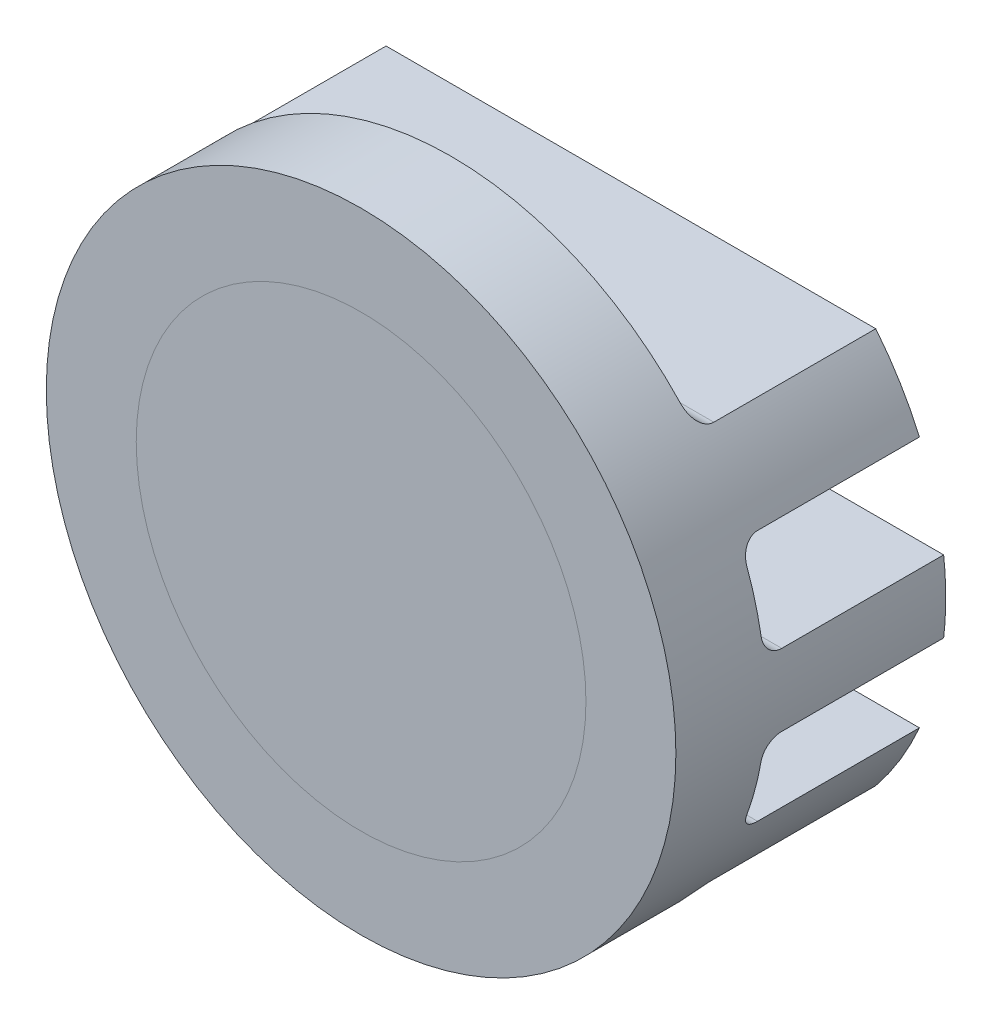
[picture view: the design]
ISO-10303-21;
HEADER;
FILE_DESCRIPTION(('STEP AP214'),'2;1');
FILE_NAME('part.step','',(''),(''),'','','');
FILE_SCHEMA(('AUTOMOTIVE_DESIGN { 1 0 10303 214 1 1 1 1 }'));
ENDSEC;
DATA;
#1=APPLICATION_CONTEXT('core data for automotive mechanical design processes');
#2=APPLICATION_PROTOCOL_DEFINITION('international standard','automotive_design',2000,#1);
#3=PRODUCT_CONTEXT('',#1,'mechanical');
#4=PRODUCT('Part','Part','',(#3));
#5=PRODUCT_RELATED_PRODUCT_CATEGORY('part','',(#4));
#6=PRODUCT_DEFINITION_FORMATION('','',#4);
#7=PRODUCT_DEFINITION_CONTEXT('part definition',#1,'design');
#8=PRODUCT_DEFINITION('design','',#6,#7);
#9=PRODUCT_DEFINITION_SHAPE('','',#8);
#10=(LENGTH_UNIT() NAMED_UNIT(*) SI_UNIT(.MILLI.,.METRE.));
#11=(NAMED_UNIT(*) PLANE_ANGLE_UNIT() SI_UNIT($,.RADIAN.));
#12=(NAMED_UNIT(*) SI_UNIT($,.STERADIAN.) SOLID_ANGLE_UNIT());
#13=UNCERTAINTY_MEASURE_WITH_UNIT(LENGTH_MEASURE(1.E-05),#10,'distance_accuracy_value','');
#14=(GEOMETRIC_REPRESENTATION_CONTEXT(3) GLOBAL_UNCERTAINTY_ASSIGNED_CONTEXT((#13)) GLOBAL_UNIT_ASSIGNED_CONTEXT((#10,
#11,#12)) REPRESENTATION_CONTEXT('',''));
#15=CARTESIAN_POINT('',(0.,0.,0.));
#16=DIRECTION('',(0.,0.,1.));
#17=DIRECTION('',(1.,0.,0.));
#18=AXIS2_PLACEMENT_3D('',#15,#16,#17);
#19=CARTESIAN_POINT('',(43.,4.,-20.));
#20=DIRECTION('',(0.,0.,1.));
#21=DIRECTION('',(1.,0.,0.));
#22=AXIS2_PLACEMENT_3D('',#19,#20,#21);
#23=PLANE('',#22);
#24=DIRECTION('',(-1.,0.,0.));
#25=VECTOR('',#24,1.);
#26=CARTESIAN_POINT('',(43.,0.,-20.));
#27=LINE('',#26,#25);
#28=CARTESIAN_POINT('',(0.,0.,-20.));
#29=VERTEX_POINT('',#28);
#30=CARTESIAN_POINT('',(-35.,0.,-20.));
#31=VERTEX_POINT('',#30);
#32=EDGE_CURVE('E12',#29,#31,#27,.T.);
#33=ORIENTED_EDGE('',*,*,#32,.F.);
#34=DIRECTION('',(0.,-1.,0.));
#35=VECTOR('',#34,1.);
#36=CARTESIAN_POINT('',(0.,4.,-20.));
#37=LINE('',#36,#35);
#38=CARTESIAN_POINT('',(0.,-4.,-20.));
#39=VERTEX_POINT('',#38);
#40=EDGE_CURVE('E357',#29,#39,#37,.T.);
#41=ORIENTED_EDGE('',*,*,#40,.T.);
#42=DIRECTION('',(-1.,0.,0.));
#43=VECTOR('',#42,1.);
#44=CARTESIAN_POINT('',(43.,-4.,-20.));
#45=LINE('',#44,#43);
#46=CARTESIAN_POINT('',(-34.7706773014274,-4.,-20.));
#47=VERTEX_POINT('',#46);
#48=EDGE_CURVE('E234',#39,#47,#45,.T.);
#49=ORIENTED_EDGE('',*,*,#48,.T.);
#50=CARTESIAN_POINT('',(0.,0.,-20.));
#51=DIRECTION('',(0.,0.,1.));
#52=DIRECTION('',(1.,0.,0.));
#53=AXIS2_PLACEMENT_3D('',#50,#51,#52);
#54=CIRCLE('',#53,35.);
#55=EDGE_CURVE('E189',#31,#47,#54,.T.);
#56=ORIENTED_EDGE('',*,*,#55,.F.);
#57=EDGE_LOOP('',(#33,#41,#49,#56));
#58=FACE_BOUND('',#57,.T.);
#59=ADVANCED_FACE('F39',(#58),#23,.F.);
#60=DIRECTION('',(-1.,0.,0.));
#61=VECTOR('',#60,1.);
#62=CARTESIAN_POINT('',(43.,0.,-20.));
#63=LINE('',#62,#61);
#64=CARTESIAN_POINT('',(35.,0.,-20.));
#65=VERTEX_POINT('',#64);
#66=EDGE_CURVE('E44',#65,#29,#63,.T.);
#67=ORIENTED_EDGE('',*,*,#66,.F.);
#68=CARTESIAN_POINT('',(34.7706773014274,-4.,-20.));
#69=VERTEX_POINT('',#68);
#70=EDGE_CURVE('E185',#69,#65,#54,.T.);
#71=ORIENTED_EDGE('',*,*,#70,.F.);
#72=EDGE_CURVE('E198',#69,#39,#45,.T.);
#73=ORIENTED_EDGE('',*,*,#72,.T.);
#74=ORIENTED_EDGE('',*,*,#40,.F.);
#75=EDGE_LOOP('',(#67,#71,#73,#74));
#76=FACE_BOUND('',#75,.T.);
#77=ADVANCED_FACE('F351',(#76),#23,.F.);
#78=CARTESIAN_POINT('',(34.7706773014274,4.,-20.));
#79=VERTEX_POINT('',#78);
#80=EDGE_CURVE('E181',#65,#79,#54,.T.);
#81=ORIENTED_EDGE('',*,*,#80,.F.);
#82=ORIENTED_EDGE('',*,*,#66,.T.);
#83=CARTESIAN_POINT('',(0.,4.,-20.));
#84=VERTEX_POINT('',#83);
#85=EDGE_CURVE('E193',#84,#29,#37,.T.);
#86=ORIENTED_EDGE('',*,*,#85,.F.);
#87=DIRECTION('',(1.,0.,0.));
#88=VECTOR('',#87,1.);
#89=CARTESIAN_POINT('',(43.,4.,-20.));
#90=LINE('',#89,#88);
#91=EDGE_CURVE('E191',#84,#79,#90,.T.);
#92=ORIENTED_EDGE('',*,*,#91,.T.);
#93=EDGE_LOOP('',(#81,#82,#86,#92));
#94=FACE_BOUND('',#93,.T.);
#95=ADVANCED_FACE('F192',(#94),#23,.F.);
#96=CARTESIAN_POINT('',(0.,0.,10.));
#97=DIRECTION('',(0.,0.,1.));
#98=DIRECTION('',(1.,0.,0.));
#99=AXIS2_PLACEMENT_3D('',#96,#97,#98);
#100=PLANE('',#99);
#101=CARTESIAN_POINT('',(0.,0.,10.));
#102=DIRECTION('',(0.,0.,1.));
#103=DIRECTION('',(1.,0.,0.));
#104=AXIS2_PLACEMENT_3D('',#101,#102,#103);
#105=CIRCLE('',#104,35.);
#106=CARTESIAN_POINT('',(35.,0.,10.));
#107=VERTEX_POINT('',#106);
#108=EDGE_CURVE('E243',#107,#107,#105,.T.);
#109=ORIENTED_EDGE('',*,*,#108,.T.);
#110=EDGE_LOOP('',(#109));
#111=FACE_BOUND('',#110,.T.);
#112=CARTESIAN_POINT('',(0.,0.,10.));
#113=DIRECTION('',(0.,0.,1.));
#114=DIRECTION('',(1.,0.,0.));
#115=AXIS2_PLACEMENT_3D('',#112,#113,#114);
#116=CIRCLE('',#115,25.);
#117=CARTESIAN_POINT('',(25.,0.,10.));
#118=VERTEX_POINT('',#117);
#119=EDGE_CURVE('E363',#118,#118,#116,.F.);
#120=ORIENTED_EDGE('',*,*,#119,.T.);
#121=EDGE_LOOP('',(#120));
#122=FACE_BOUND('',#121,.T.);
#123=ADVANCED_FACE('F334',(#111,#122),#100,.T.);
#124=CARTESIAN_POINT('',(43.,-4.,-20.));
#125=DIRECTION('',(0.,1.,0.));
#126=DIRECTION('',(0.,0.,1.));
#127=AXIS2_PLACEMENT_3D('',#124,#125,#126);
#128=PLANE('',#127);
#129=DIRECTION('',(0.,0.,1.));
#130=VECTOR('',#129,1.);
#131=CARTESIAN_POINT('',(34.7706773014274,-4.,-20.));
#132=LINE('',#131,#130);
#133=CARTESIAN_POINT('',(34.7706773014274,-4.,-2.));
#134=VERTEX_POINT('',#133);
#135=EDGE_CURVE('E217',#134,#69,#132,.F.);
#136=ORIENTED_EDGE('',*,*,#135,.F.);
#137=DIRECTION('',(-1.,0.,0.));
#138=VECTOR('',#137,1.);
#139=CARTESIAN_POINT('',(-34.7706773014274,-4.,-2.));
#140=LINE('',#139,#138);
#141=CARTESIAN_POINT('',(-34.7706773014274,-4.,-2.));
#142=VERTEX_POINT('',#141);
#143=EDGE_CURVE('E264',#134,#142,#140,.T.);
#144=ORIENTED_EDGE('',*,*,#143,.T.);
#145=DIRECTION('',(0.,0.,1.));
#146=VECTOR('',#145,1.);
#147=CARTESIAN_POINT('',(-34.7706773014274,-4.,-20.));
#148=LINE('',#147,#146);
#149=EDGE_CURVE('E219',#47,#142,#148,.T.);
#150=ORIENTED_EDGE('',*,*,#149,.F.);
#151=ORIENTED_EDGE('',*,*,#48,.F.);
#152=ORIENTED_EDGE('',*,*,#72,.F.);
#153=EDGE_LOOP('',(#136,#144,#150,#151,#152));
#154=FACE_BOUND('',#153,.T.);
#155=ADVANCED_FACE('F331',(#154),#128,.F.);
#156=CARTESIAN_POINT('',(43.,4.,-20.));
#157=DIRECTION('',(0.,-1.,0.));
#158=DIRECTION('',(0.,0.,-1.));
#159=AXIS2_PLACEMENT_3D('',#156,#157,#158);
#160=PLANE('',#159);
#161=DIRECTION('',(0.,0.,1.));
#162=VECTOR('',#161,1.);
#163=CARTESIAN_POINT('',(-34.7706773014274,4.,-20.));
#164=LINE('',#163,#162);
#165=CARTESIAN_POINT('',(-34.7706773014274,4.,-2.));
#166=VERTEX_POINT('',#165);
#167=CARTESIAN_POINT('',(-34.7706773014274,4.,-20.));
#168=VERTEX_POINT('',#167);
#169=EDGE_CURVE('E211',#166,#168,#164,.F.);
#170=ORIENTED_EDGE('',*,*,#169,.F.);
#171=DIRECTION('',(1.,0.,0.));
#172=VECTOR('',#171,1.);
#173=CARTESIAN_POINT('',(34.7706773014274,4.,-2.));
#174=LINE('',#173,#172);
#175=CARTESIAN_POINT('',(34.7706773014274,4.,-2.));
#176=VERTEX_POINT('',#175);
#177=EDGE_CURVE('E204',#166,#176,#174,.T.);
#178=ORIENTED_EDGE('',*,*,#177,.T.);
#179=DIRECTION('',(0.,0.,1.));
#180=VECTOR('',#179,1.);
#181=CARTESIAN_POINT('',(34.7706773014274,4.,-20.));
#182=LINE('',#181,#180);
#183=EDGE_CURVE('E184',#79,#176,#182,.T.);
#184=ORIENTED_EDGE('',*,*,#183,.F.);
#185=ORIENTED_EDGE('',*,*,#91,.F.);
#186=EDGE_CURVE('E197',#168,#84,#90,.T.);
#187=ORIENTED_EDGE('',*,*,#186,.F.);
#188=EDGE_LOOP('',(#170,#178,#184,#185,#187));
#189=FACE_BOUND('',#188,.T.);
#190=ADVANCED_FACE('F202',(#189),#160,.F.);
#191=ORIENTED_EDGE('',*,*,#85,.T.);
#192=ORIENTED_EDGE('',*,*,#32,.T.);
#193=EDGE_CURVE('E188',#168,#31,#54,.T.);
#194=ORIENTED_EDGE('',*,*,#193,.F.);
#195=ORIENTED_EDGE('',*,*,#186,.T.);
#196=EDGE_LOOP('',(#191,#192,#194,#195));
#197=FACE_BOUND('',#196,.T.);
#198=ADVANCED_FACE('F325',(#197),#23,.F.);
#199=CARTESIAN_POINT('',(43.,14.,-20.));
#200=DIRECTION('',(0.,1.,0.));
#201=DIRECTION('',(0.,0.,1.));
#202=AXIS2_PLACEMENT_3D('',#199,#200,#201);
#203=PLANE('',#202);
#204=DIRECTION('',(0.,0.,1.));
#205=VECTOR('',#204,1.);
#206=CARTESIAN_POINT('',(32.0780298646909,14.,-20.));
#207=LINE('',#206,#205);
#208=CARTESIAN_POINT('',(32.0780298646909,14.,-2.));
#209=VERTEX_POINT('',#208);
#210=CARTESIAN_POINT('',(32.0780298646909,14.,-20.));
#211=VERTEX_POINT('',#210);
#212=EDGE_CURVE('E205',#209,#211,#207,.F.);
#213=ORIENTED_EDGE('',*,*,#212,.F.);
#214=DIRECTION('',(-1.,0.,0.));
#215=VECTOR('',#214,1.);
#216=CARTESIAN_POINT('',(-32.0780298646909,14.,-2.));
#217=LINE('',#216,#215);
#218=CARTESIAN_POINT('',(-32.0780298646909,14.,-2.));
#219=VERTEX_POINT('',#218);
#220=EDGE_CURVE('E256',#209,#219,#217,.T.);
#221=ORIENTED_EDGE('',*,*,#220,.T.);
#222=DIRECTION('',(0.,0.,1.));
#223=VECTOR('',#222,1.);
#224=CARTESIAN_POINT('',(-32.0780298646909,14.,-20.));
#225=LINE('',#224,#223);
#226=CARTESIAN_POINT('',(-32.0780298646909,14.,-20.));
#227=VERTEX_POINT('',#226);
#228=EDGE_CURVE('E208',#227,#219,#225,.T.);
#229=ORIENTED_EDGE('',*,*,#228,.F.);
#230=DIRECTION('',(-1.,0.,0.));
#231=VECTOR('',#230,1.);
#232=CARTESIAN_POINT('',(43.,14.,-20.));
#233=LINE('',#232,#231);
#234=EDGE_CURVE('E228',#211,#227,#233,.T.);
#235=ORIENTED_EDGE('',*,*,#234,.F.);
#236=EDGE_LOOP('',(#213,#221,#229,#235));
#237=FACE_BOUND('',#236,.T.);
#238=ADVANCED_FACE('F321',(#237),#203,.F.);
#239=CARTESIAN_POINT('',(43.,22.,-20.));
#240=DIRECTION('',(0.,-1.,0.));
#241=DIRECTION('',(0.,0.,-1.));
#242=AXIS2_PLACEMENT_3D('',#239,#240,#241);
#243=PLANE('',#242);
#244=DIRECTION('',(0.,0.,1.));
#245=VECTOR('',#244,1.);
#246=CARTESIAN_POINT('',(-27.2213151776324,22.,-20.));
#247=LINE('',#246,#245);
#248=CARTESIAN_POINT('',(-27.2213151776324,22.,-2.));
#249=VERTEX_POINT('',#248);
#250=CARTESIAN_POINT('',(-27.2213151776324,22.,-20.));
#251=VERTEX_POINT('',#250);
#252=EDGE_CURVE('E451',#249,#251,#247,.F.);
#253=ORIENTED_EDGE('',*,*,#252,.F.);
#254=DIRECTION('',(1.,0.,0.));
#255=VECTOR('',#254,1.);
#256=CARTESIAN_POINT('',(27.2213151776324,22.,-2.));
#257=LINE('',#256,#255);
#258=CARTESIAN_POINT('',(27.2213151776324,22.,-2.));
#259=VERTEX_POINT('',#258);
#260=EDGE_CURVE('E251',#249,#259,#257,.T.);
#261=ORIENTED_EDGE('',*,*,#260,.T.);
#262=DIRECTION('',(0.,0.,1.));
#263=VECTOR('',#262,1.);
#264=CARTESIAN_POINT('',(27.2213151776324,22.,-20.));
#265=LINE('',#264,#263);
#266=CARTESIAN_POINT('',(27.2213151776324,22.,-20.));
#267=VERTEX_POINT('',#266);
#268=EDGE_CURVE('E206',#267,#259,#265,.T.);
#269=ORIENTED_EDGE('',*,*,#268,.F.);
#270=DIRECTION('',(1.,0.,0.));
#271=VECTOR('',#270,1.);
#272=CARTESIAN_POINT('',(43.,22.,-20.));
#273=LINE('',#272,#271);
#274=EDGE_CURVE('E231',#251,#267,#273,.T.);
#275=ORIENTED_EDGE('',*,*,#274,.F.);
#276=EDGE_LOOP('',(#253,#261,#269,#275));
#277=FACE_BOUND('',#276,.T.);
#278=ADVANCED_FACE('F317',(#277),#243,.F.);
#279=CARTESIAN_POINT('',(43.,22.,-20.));
#280=DIRECTION('',(0.,0.,1.));
#281=DIRECTION('',(1.,0.,0.));
#282=AXIS2_PLACEMENT_3D('',#279,#280,#281);
#283=PLANE('',#282);
#284=EDGE_CURVE('E462',#211,#267,#54,.T.);
#285=ORIENTED_EDGE('',*,*,#284,.F.);
#286=ORIENTED_EDGE('',*,*,#234,.T.);
#287=EDGE_CURVE('E463',#251,#227,#54,.T.);
#288=ORIENTED_EDGE('',*,*,#287,.F.);
#289=ORIENTED_EDGE('',*,*,#274,.T.);
#290=EDGE_LOOP('',(#285,#286,#288,#289));
#291=FACE_BOUND('',#290,.T.);
#292=ADVANCED_FACE('F313',(#291),#283,.F.);
#293=CARTESIAN_POINT('',(43.,-22.,-20.));
#294=DIRECTION('',(0.,-1.,0.));
#295=DIRECTION('',(0.,0.,-1.));
#296=AXIS2_PLACEMENT_3D('',#293,#294,#295);
#297=PLANE('',#296);
#298=DIRECTION('',(0.,0.,1.));
#299=VECTOR('',#298,1.);
#300=CARTESIAN_POINT('',(27.2213151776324,-22.,-20.));
#301=LINE('',#300,#299);
#302=CARTESIAN_POINT('',(27.2213151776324,-22.,-20.));
#303=VERTEX_POINT('',#302);
#304=CARTESIAN_POINT('',(27.2213151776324,-22.,-2.));
#305=VERTEX_POINT('',#304);
#306=EDGE_CURVE('E452',#303,#305,#301,.T.);
#307=ORIENTED_EDGE('',*,*,#306,.T.);
#308=DIRECTION('',(1.,0.,0.));
#309=VECTOR('',#308,1.);
#310=CARTESIAN_POINT('',(43.,-22.,-2.));
#311=LINE('',#310,#309);
#312=CARTESIAN_POINT('',(-27.2213151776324,-22.,-2.));
#313=VERTEX_POINT('',#312);
#314=EDGE_CURVE('E277',#305,#313,#311,.F.);
#315=ORIENTED_EDGE('',*,*,#314,.T.);
#316=DIRECTION('',(0.,0.,1.));
#317=VECTOR('',#316,1.);
#318=CARTESIAN_POINT('',(-27.2213151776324,-22.,-20.));
#319=LINE('',#318,#317);
#320=CARTESIAN_POINT('',(-27.2213151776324,-22.,-20.));
#321=VERTEX_POINT('',#320);
#322=EDGE_CURVE('E459',#313,#321,#319,.F.);
#323=ORIENTED_EDGE('',*,*,#322,.T.);
#324=DIRECTION('',(1.,0.,0.));
#325=VECTOR('',#324,1.);
#326=CARTESIAN_POINT('',(43.,-22.,-20.));
#327=LINE('',#326,#325);
#328=EDGE_CURVE('E222',#321,#303,#327,.T.);
#329=ORIENTED_EDGE('',*,*,#328,.T.);
#330=EDGE_LOOP('',(#307,#315,#323,#329));
#331=FACE_BOUND('',#330,.T.);
#332=ADVANCED_FACE('F309',(#331),#297,.T.);
#333=CARTESIAN_POINT('',(43.,-14.,-20.));
#334=DIRECTION('',(0.,1.,0.));
#335=DIRECTION('',(0.,0.,1.));
#336=AXIS2_PLACEMENT_3D('',#333,#334,#335);
#337=PLANE('',#336);
#338=DIRECTION('',(0.,0.,1.));
#339=VECTOR('',#338,1.);
#340=CARTESIAN_POINT('',(-32.0780298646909,-14.,-20.));
#341=LINE('',#340,#339);
#342=CARTESIAN_POINT('',(-32.0780298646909,-14.,-20.));
#343=VERTEX_POINT('',#342);
#344=CARTESIAN_POINT('',(-32.0780298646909,-14.,-2.));
#345=VERTEX_POINT('',#344);
#346=EDGE_CURVE('E457',#343,#345,#341,.T.);
#347=ORIENTED_EDGE('',*,*,#346,.T.);
#348=DIRECTION('',(-1.,0.,0.));
#349=VECTOR('',#348,1.);
#350=CARTESIAN_POINT('',(43.,-14.,-2.));
#351=LINE('',#350,#349);
#352=CARTESIAN_POINT('',(32.0780298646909,-14.,-2.));
#353=VERTEX_POINT('',#352);
#354=EDGE_CURVE('E272',#345,#353,#351,.F.);
#355=ORIENTED_EDGE('',*,*,#354,.T.);
#356=DIRECTION('',(0.,0.,1.));
#357=VECTOR('',#356,1.);
#358=CARTESIAN_POINT('',(32.0780298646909,-14.,-20.));
#359=LINE('',#358,#357);
#360=CARTESIAN_POINT('',(32.0780298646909,-14.,-20.));
#361=VERTEX_POINT('',#360);
#362=EDGE_CURVE('E461',#353,#361,#359,.F.);
#363=ORIENTED_EDGE('',*,*,#362,.T.);
#364=DIRECTION('',(-1.,0.,0.));
#365=VECTOR('',#364,1.);
#366=CARTESIAN_POINT('',(43.,-14.,-20.));
#367=LINE('',#366,#365);
#368=EDGE_CURVE('E225',#361,#343,#367,.T.);
#369=ORIENTED_EDGE('',*,*,#368,.T.);
#370=EDGE_LOOP('',(#347,#355,#363,#369));
#371=FACE_BOUND('',#370,.T.);
#372=ADVANCED_FACE('F305',(#371),#337,.T.);
#373=CARTESIAN_POINT('',(43.,-22.,-20.));
#374=DIRECTION('',(0.,0.,1.));
#375=DIRECTION('',(1.,0.,0.));
#376=AXIS2_PLACEMENT_3D('',#373,#374,#375);
#377=PLANE('',#376);
#378=CARTESIAN_POINT('',(0.,0.,-20.));
#379=DIRECTION('',(0.,0.,1.));
#380=DIRECTION('',(1.,0.,0.));
#381=AXIS2_PLACEMENT_3D('',#378,#379,#380);
#382=CIRCLE('',#381,35.);
#383=EDGE_CURVE('E250',#343,#321,#382,.T.);
#384=ORIENTED_EDGE('',*,*,#383,.F.);
#385=ORIENTED_EDGE('',*,*,#368,.F.);
#386=EDGE_CURVE('E246',#303,#361,#382,.T.);
#387=ORIENTED_EDGE('',*,*,#386,.F.);
#388=ORIENTED_EDGE('',*,*,#328,.F.);
#389=EDGE_LOOP('',(#384,#385,#387,#388));
#390=FACE_BOUND('',#389,.T.);
#391=ADVANCED_FACE('F300',(#390),#377,.F.);
#392=CARTESIAN_POINT('',(0.,0.,0.));
#393=DIRECTION('',(0.,0.,1.));
#394=DIRECTION('',(1.,0.,0.));
#395=AXIS2_PLACEMENT_3D('',#392,#393,#394);
#396=PLANE('',#395);
#397=CARTESIAN_POINT('',(0.,0.,0.));
#398=DIRECTION('',(0.,0.,1.));
#399=DIRECTION('',(1.,0.,0.));
#400=AXIS2_PLACEMENT_3D('',#397,#398,#399);
#401=CIRCLE('',#400,35.);
#402=CARTESIAN_POINT('',(-25.475478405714,-24.,0.));
#403=VERTEX_POINT('',#402);
#404=CARTESIAN_POINT('',(25.475478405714,-24.,0.));
#405=VERTEX_POINT('',#404);
#406=EDGE_CURVE('E238',#403,#405,#401,.T.);
#407=ORIENTED_EDGE('',*,*,#406,.F.);
#408=DIRECTION('',(1.,0.,0.));
#409=VECTOR('',#408,1.);
#410=CARTESIAN_POINT('',(0.,-24.,0.));
#411=LINE('',#410,#409);
#412=EDGE_CURVE('E274',#403,#405,#411,.T.);
#413=ORIENTED_EDGE('',*,*,#412,.T.);
#414=EDGE_LOOP('',(#407,#413));
#415=FACE_BOUND('',#414,.T.);
#416=ADVANCED_FACE('F304',(#415),#396,.F.);
#417=CARTESIAN_POINT('',(-32.8785644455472,12.,0.));
#418=VERTEX_POINT('',#417);
#419=CARTESIAN_POINT('',(-34.4818792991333,6.,0.));
#420=VERTEX_POINT('',#419);
#421=EDGE_CURVE('E450',#418,#420,#401,.T.);
#422=ORIENTED_EDGE('',*,*,#421,.F.);
#423=DIRECTION('',(-1.,0.,0.));
#424=VECTOR('',#423,1.);
#425=CARTESIAN_POINT('',(32.0780298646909,12.,0.));
#426=LINE('',#425,#424);
#427=CARTESIAN_POINT('',(32.8785644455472,12.,0.));
#428=VERTEX_POINT('',#427);
#429=EDGE_CURVE('E261',#418,#428,#426,.F.);
#430=ORIENTED_EDGE('',*,*,#429,.T.);
#431=CARTESIAN_POINT('',(34.4818792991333,6.,0.));
#432=VERTEX_POINT('',#431);
#433=EDGE_CURVE('E247',#432,#428,#401,.T.);
#434=ORIENTED_EDGE('',*,*,#433,.F.);
#435=DIRECTION('',(1.,0.,0.));
#436=VECTOR('',#435,1.);
#437=CARTESIAN_POINT('',(-34.7706773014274,6.,0.));
#438=LINE('',#437,#436);
#439=EDGE_CURVE('E259',#432,#420,#438,.F.);
#440=ORIENTED_EDGE('',*,*,#439,.T.);
#441=EDGE_LOOP('',(#422,#430,#434,#440));
#442=FACE_BOUND('',#441,.T.);
#443=ADVANCED_FACE('F336',(#442),#396,.F.);
#444=CARTESIAN_POINT('',(25.475478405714,24.,0.));
#445=VERTEX_POINT('',#444);
#446=CARTESIAN_POINT('',(-25.475478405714,24.,0.));
#447=VERTEX_POINT('',#446);
#448=EDGE_CURVE('E242',#445,#447,#401,.T.);
#449=ORIENTED_EDGE('',*,*,#448,.F.);
#450=DIRECTION('',(1.,0.,0.));
#451=VECTOR('',#450,1.);
#452=CARTESIAN_POINT('',(-27.2213151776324,24.,0.));
#453=LINE('',#452,#451);
#454=EDGE_CURVE('E254',#445,#447,#453,.F.);
#455=ORIENTED_EDGE('',*,*,#454,.T.);
#456=EDGE_LOOP('',(#449,#455));
#457=FACE_BOUND('',#456,.T.);
#458=ADVANCED_FACE('F338',(#457),#396,.F.);
#459=CARTESIAN_POINT('',(-34.4818792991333,-6.,0.));
#460=VERTEX_POINT('',#459);
#461=CARTESIAN_POINT('',(-32.8785644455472,-12.,0.));
#462=VERTEX_POINT('',#461);
#463=EDGE_CURVE('E241',#460,#462,#401,.T.);
#464=ORIENTED_EDGE('',*,*,#463,.F.);
#465=DIRECTION('',(-1.,0.,0.));
#466=VECTOR('',#465,1.);
#467=CARTESIAN_POINT('',(34.7706773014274,-6.,0.));
#468=LINE('',#467,#466);
#469=CARTESIAN_POINT('',(34.4818792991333,-6.,0.));
#470=VERTEX_POINT('',#469);
#471=EDGE_CURVE('E270',#460,#470,#468,.F.);
#472=ORIENTED_EDGE('',*,*,#471,.T.);
#473=CARTESIAN_POINT('',(32.8785644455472,-12.,0.));
#474=VERTEX_POINT('',#473);
#475=EDGE_CURVE('E237',#474,#470,#401,.T.);
#476=ORIENTED_EDGE('',*,*,#475,.F.);
#477=DIRECTION('',(-1.,0.,0.));
#478=VECTOR('',#477,1.);
#479=CARTESIAN_POINT('',(0.,-12.,0.));
#480=LINE('',#479,#478);
#481=EDGE_CURVE('E267',#474,#462,#480,.T.);
#482=ORIENTED_EDGE('',*,*,#481,.T.);
#483=EDGE_LOOP('',(#464,#472,#476,#482));
#484=FACE_BOUND('',#483,.T.);
#485=ADVANCED_FACE('F340',(#484),#396,.F.);
#486=CARTESIAN_POINT('',(0.,0.,10.));
#487=DIRECTION('',(0.,0.,-1.));
#488=DIRECTION('',(-1.,0.,0.));
#489=AXIS2_PLACEMENT_3D('',#486,#487,#488);
#490=CYLINDRICAL_SURFACE('',#489,35.);
#491=ORIENTED_EDGE('',*,*,#108,.F.);
#492=EDGE_LOOP('',(#491));
#493=FACE_BOUND('',#492,.T.);
#494=ORIENTED_EDGE('',*,*,#183,.T.);
#495=CARTESIAN_POINT('',(34.7706773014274,4.,-2.));
#496=CARTESIAN_POINT('',(34.770676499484,4.00000018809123,-1.94404006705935));
#497=CARTESIAN_POINT('',(34.7704070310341,4.00235013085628,-1.88810699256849));
#498=CARTESIAN_POINT('',(34.7693270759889,4.01172376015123,-1.77664227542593));
#499=CARTESIAN_POINT('',(34.7685166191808,4.01874718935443,-1.72111061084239));
#500=CARTESIAN_POINT('',(34.7652720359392,4.0467562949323,-1.55582564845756));
#501=CARTESIAN_POINT('',(34.7620247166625,4.07468100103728,-1.44718144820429));
#502=CARTESIAN_POINT('',(34.7533243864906,4.14822840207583,-1.23616117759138));
#503=CARTESIAN_POINT('',(34.7478703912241,4.1938589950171,-1.13378792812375));
#504=CARTESIAN_POINT('',(34.7347132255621,4.30146761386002,-0.93819121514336));
#505=CARTESIAN_POINT('',(34.7270103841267,4.36344324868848,-0.844966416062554));
#506=CARTESIAN_POINT('',(34.7093131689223,4.50205004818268,-0.670105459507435));
#507=CARTESIAN_POINT('',(34.6993145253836,4.57870847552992,-0.588491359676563));
#508=CARTESIAN_POINT('',(34.6770513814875,4.7443732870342,-0.439285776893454));
#509=CARTESIAN_POINT('',(34.6647864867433,4.83338181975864,-0.371696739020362));
#510=CARTESIAN_POINT('',(34.6380026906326,5.02173930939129,-0.251989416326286));
#511=CARTESIAN_POINT('',(34.6234700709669,5.12114989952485,-0.199971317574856));
#512=CARTESIAN_POINT('',(34.592399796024,5.32697713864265,-0.113337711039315));
#513=CARTESIAN_POINT('',(34.5758628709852,5.43339122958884,-0.078715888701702));
#514=CARTESIAN_POINT('',(34.5464284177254,5.61694672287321,-0.0355031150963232));
#515=CARTESIAN_POINT('',(34.5339655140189,5.69308232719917,-0.0221886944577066));
#516=CARTESIAN_POINT('',(34.508384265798,5.84615233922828,-0.00443801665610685));
#517=CARTESIAN_POINT('',(34.4952669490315,5.92308535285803,1.17387582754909E-05));
#518=CARTESIAN_POINT('',(34.4818792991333,6.,0.));
#519=B_SPLINE_CURVE_WITH_KNOTS('',3,(#495,#496,#497,#498,#499,#500,#501,#502,#503,#504,#505,
#506,#507,#508,#509,#510,#511,#512,#513,#514,#515,#516,#517,#518),.UNSPECIFIED.,.F.,.F.,(4,2,2,
2,2,2,2,2,2,2,2,4),(0.,0.167776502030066,0.335543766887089,0.670483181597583,1.00557217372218,
1.34061217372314,1.67628040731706,2.0120071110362,2.34984966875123,2.68756950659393,
2.92195601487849,3.15598534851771),.UNSPECIFIED.);
#520=EDGE_CURVE('E430',#176,#432,#519,.T.);
#521=ORIENTED_EDGE('',*,*,#520,.T.);
#522=ORIENTED_EDGE('',*,*,#433,.T.);
#523=CARTESIAN_POINT('',(32.8785644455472,12.,0.));
#524=CARTESIAN_POINT('',(32.8567375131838,12.0598059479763,-2.54975750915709E-06));
#525=CARTESIAN_POINT('',(32.8347564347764,12.1195214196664,-0.00268385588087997));
#526=CARTESIAN_POINT('',(32.7906280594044,12.238411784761,-0.0133628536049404));
#527=CARTESIAN_POINT('',(32.7684807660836,12.2975866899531,-0.021360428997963));
#528=CARTESIAN_POINT('',(32.7020073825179,12.4737487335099,-0.0532630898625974));
#529=CARTESIAN_POINT('',(32.6576436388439,12.5893900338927,-0.0850781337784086));
#530=CARTESIAN_POINT('',(32.5703141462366,12.8136318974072,-0.169053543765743));
#531=CARTESIAN_POINT('',(32.5273492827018,12.9222280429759,-0.221226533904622));
#532=CARTESIAN_POINT('',(32.4443956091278,13.1291129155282,-0.344825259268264));
#533=CARTESIAN_POINT('',(32.4044055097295,13.2274061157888,-0.416242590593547));
#534=CARTESIAN_POINT('',(32.3299365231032,13.4083774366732,-0.574994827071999));
#535=CARTESIAN_POINT('',(32.2953544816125,13.4913553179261,-0.661938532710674));
#536=CARTESIAN_POINT('',(32.232331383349,13.6412405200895,-0.850724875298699));
#537=CARTESIAN_POINT('',(32.2038894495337,13.7081501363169,-0.952565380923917));
#538=CARTESIAN_POINT('',(32.1565315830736,13.8188588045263,-1.16056427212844));
#539=CARTESIAN_POINT('',(32.1370855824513,13.8639542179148,-1.26591258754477));
#540=CARTESIAN_POINT('',(32.1060821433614,13.9356033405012,-1.48374243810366));
#541=CARTESIAN_POINT('',(32.0945098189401,13.9621920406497,-1.59621007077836));
#542=CARTESIAN_POINT('',(32.0841707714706,13.9859225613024,-1.75818304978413));
#543=CARTESIAN_POINT('',(32.0818694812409,13.9911996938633,-1.80639970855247));
#544=CARTESIAN_POINT('',(32.0788001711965,13.9982352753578,-1.9030686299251));
#545=CARTESIAN_POINT('',(32.0780299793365,13.9999987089,-1.95152046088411));
#546=CARTESIAN_POINT('',(32.0780298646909,14.,-2.));
#547=B_SPLINE_CURVE_WITH_KNOTS('',3,(#523,#524,#525,#526,#527,#528,#529,#530,#531,#532,#533,
#534,#535,#536,#537,#538,#539,#540,#541,#542,#543,#544,#545,#546),.UNSPECIFIED.,.F.,.F.,(4,2,2,
2,2,2,2,2,2,2,2,4),(0.,0.190873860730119,0.38174354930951,0.763429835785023,1.14535318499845,
1.5271100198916,1.90033924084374,2.27351511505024,2.6203923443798,2.96661193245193,
3.11216426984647,3.25750997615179),.UNSPECIFIED.);
#548=EDGE_CURVE('E501',#428,#209,#547,.T.);
#549=ORIENTED_EDGE('',*,*,#548,.T.);
#550=ORIENTED_EDGE('',*,*,#212,.T.);
#551=ORIENTED_EDGE('',*,*,#284,.T.);
#552=ORIENTED_EDGE('',*,*,#268,.T.);
#553=CARTESIAN_POINT('',(27.2213151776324,22.,-2.));
#554=CARTESIAN_POINT('',(27.2213222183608,21.9999899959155,-1.95280063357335));
#555=CARTESIAN_POINT('',(27.2199650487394,22.0016705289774,-1.90560753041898));
#556=CARTESIAN_POINT('',(27.2145764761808,22.0083361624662,-1.81163213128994));
#557=CARTESIAN_POINT('',(27.210546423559,22.0133195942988,-1.76484963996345));
#558=CARTESIAN_POINT('',(27.1998984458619,22.0264747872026,-1.67232577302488));
#559=CARTESIAN_POINT('',(27.1932963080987,22.0346270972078,-1.62657981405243));
#560=CARTESIAN_POINT('',(27.1776070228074,22.0539754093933,-1.53618088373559));
#561=CARTESIAN_POINT('',(27.1685196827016,22.0651716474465,-1.49152799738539));
#562=CARTESIAN_POINT('',(27.1377406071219,22.1030337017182,-1.35982018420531));
#563=CARTESIAN_POINT('',(27.1125030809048,22.1340085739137,-1.2747732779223));
#564=CARTESIAN_POINT('',(27.0537782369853,22.2057474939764,-1.11196467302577));
#565=CARTESIAN_POINT('',(27.0202798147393,22.2465247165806,-1.03421297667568));
#566=CARTESIAN_POINT('',(26.9437634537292,22.3391461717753,-0.881946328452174));
#567=CARTESIAN_POINT('',(26.9002449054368,22.3915634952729,-0.808034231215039));
#568=CARTESIAN_POINT('',(26.8067869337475,22.5033664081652,-0.670351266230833));
#569=CARTESIAN_POINT('',(26.7568467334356,22.5627528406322,-0.606581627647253));
#570=CARTESIAN_POINT('',(26.6248974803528,22.7184911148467,-0.459091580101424));
#571=CARTESIAN_POINT('',(26.539560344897,22.8182018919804,-0.381872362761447));
#572=CARTESIAN_POINT('',(26.3603969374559,23.0249493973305,-0.249447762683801));
#573=CARTESIAN_POINT('',(26.2665372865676,23.1320144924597,-0.194333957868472));
#574=CARTESIAN_POINT('',(26.1144699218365,23.3032506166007,-0.12407469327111));
#575=CARTESIAN_POINT('',(26.0580900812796,23.3662840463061,-0.101901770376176));
#576=CARTESIAN_POINT('',(25.9438580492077,23.4930521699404,-0.0641855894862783));
#577=CARTESIAN_POINT('',(25.8860053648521,23.5567870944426,-0.0486445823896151));
#578=CARTESIAN_POINT('',(25.7697572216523,23.6838965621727,-0.0240867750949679));
#579=CARTESIAN_POINT('',(25.7113717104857,23.747268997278,-0.0150110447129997));
#580=CARTESIAN_POINT('',(25.5938924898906,23.8738383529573,-0.00297434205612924));
#581=CARTESIAN_POINT('',(25.5347994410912,23.9370353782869,-8.05451722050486E-06));
#582=CARTESIAN_POINT('',(25.475478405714,24.,0.));
#583=B_SPLINE_CURVE_WITH_KNOTS('',3,(#553,#554,#555,#556,#557,#558,#559,#560,#561,#562,#563,
#564,#565,#566,#567,#568,#569,#570,#571,#572,#573,#574,#575,#576,#577,#578,#579,#580,#581,#582),
.UNSPECIFIED.,.F.,.F.,(4,2,2,2,2,2,2,2,2,2,2,2,2,2,4),(0.,0.141538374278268,0.283005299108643,
0.423617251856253,0.56424010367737,0.844754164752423,1.12564737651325,1.42610944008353,
1.72660788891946,2.18095596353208,2.63716732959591,2.89921476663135,3.16135107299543,
3.42106635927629,3.68055559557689),.UNSPECIFIED.);
#584=EDGE_CURVE('E279',#259,#445,#583,.T.);
#585=ORIENTED_EDGE('',*,*,#584,.T.);
#586=ORIENTED_EDGE('',*,*,#448,.T.);
#587=CARTESIAN_POINT('',(-25.475478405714,24.,0.));
#588=CARTESIAN_POINT('',(-25.533136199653,23.9388004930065,-7.24315117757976E-06));
#589=CARTESIAN_POINT('',(-25.5905781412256,23.8773823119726,-0.00280986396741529));
#590=CARTESIAN_POINT('',(-25.7047973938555,23.7543765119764,-0.0141763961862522));
#591=CARTESIAN_POINT('',(-25.7615741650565,23.6927887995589,-0.0227446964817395));
#592=CARTESIAN_POINT('',(-25.874579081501,23.5693279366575,-0.0459033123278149));
#593=CARTESIAN_POINT('',(-25.9307995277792,23.5074562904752,-0.0605399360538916));
#594=CARTESIAN_POINT('',(-26.0418851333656,23.3843345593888,-0.0960406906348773));
#595=CARTESIAN_POINT('',(-26.0967506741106,23.3230843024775,-0.116903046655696));
#596=CARTESIAN_POINT('',(-26.2464819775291,23.1547582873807,-0.183694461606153));
#597=CARTESIAN_POINT('',(-26.3395887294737,23.0487442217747,-0.236550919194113));
#598=CARTESIAN_POINT('',(-26.5177862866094,22.8434981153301,-0.363837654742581));
#599=CARTESIAN_POINT('',(-26.6028992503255,22.744247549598,-0.438205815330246));
#600=CARTESIAN_POINT('',(-26.744639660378,22.5772791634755,-0.590843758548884));
#601=CARTESIAN_POINT('',(-26.8034317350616,22.5074044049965,-0.664727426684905));
#602=CARTESIAN_POINT('',(-26.9121598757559,22.3772836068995,-0.826322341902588));
#603=CARTESIAN_POINT('',(-26.9621030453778,22.3170298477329,-0.91402238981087));
#604=CARTESIAN_POINT('',(-27.0432813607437,22.2185579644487,-1.08643358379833));
#605=CARTESIAN_POINT('',(-27.0762491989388,22.1783390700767,-1.16918059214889));
#606=CARTESIAN_POINT('',(-27.1328826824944,22.109018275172,-1.34210029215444));
#607=CARTESIAN_POINT('',(-27.1565642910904,22.0798972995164,-1.43225991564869));
#608=CARTESIAN_POINT('',(-27.1901715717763,22.0384925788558,-1.60162359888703));
#609=CARTESIAN_POINT('',(-27.2017777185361,22.0241560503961,-1.67998962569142));
#610=CARTESIAN_POINT('',(-27.2134615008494,22.0097148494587,-1.79905868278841));
#611=CARTESIAN_POINT('',(-27.2164019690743,22.0060782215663,-1.83908957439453));
#612=CARTESIAN_POINT('',(-27.2203301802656,22.0012188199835,-1.91940869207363));
#613=CARTESIAN_POINT('',(-27.2213171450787,21.9999970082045,-1.95969701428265));
#614=CARTESIAN_POINT('',(-27.2213151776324,22.,-2.));
#615=B_SPLINE_CURVE_WITH_KNOTS('',3,(#587,#588,#589,#590,#591,#592,#593,#594,#595,#596,#597,
#598,#599,#600,#601,#602,#603,#604,#605,#606,#607,#608,#609,#610,#611,#612,#613,#614),
.UNSPECIFIED.,.F.,.F.,(4,2,2,2,2,2,2,2,2,2,2,2,2,4),(0.,0.252215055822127,0.504622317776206,
0.758992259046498,1.01328975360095,1.46356423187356,1.91255125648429,2.26364318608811,
2.61445198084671,2.90644391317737,3.19793168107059,3.43849242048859,3.55929428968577,
3.68014426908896),.UNSPECIFIED.);
#616=EDGE_CURVE('E285',#447,#249,#615,.T.);
#617=ORIENTED_EDGE('',*,*,#616,.T.);
#618=ORIENTED_EDGE('',*,*,#252,.T.);
#619=ORIENTED_EDGE('',*,*,#287,.T.);
#620=ORIENTED_EDGE('',*,*,#228,.T.);
#621=CARTESIAN_POINT('',(-32.0780298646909,14.,-2.));
#622=CARTESIAN_POINT('',(-32.0780254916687,14.0000076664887,-1.94697972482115));
#623=CARTESIAN_POINT('',(-32.0789499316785,13.9978918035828,-1.89396375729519));
#624=CARTESIAN_POINT('',(-32.082623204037,13.9894720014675,-1.788341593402));
#625=CARTESIAN_POINT('',(-32.0853715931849,13.9831690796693,-1.73573530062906));
#626=CARTESIAN_POINT('',(-32.0926480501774,13.9664605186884,-1.63147242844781));
#627=CARTESIAN_POINT('',(-32.0971704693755,13.9560679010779,-1.57981337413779));
#628=CARTESIAN_POINT('',(-32.1079280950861,13.9313005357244,-1.47765459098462));
#629=CARTESIAN_POINT('',(-32.1141633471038,13.9169256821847,-1.42715489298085));
#630=CARTESIAN_POINT('',(-32.1353176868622,13.8680435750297,-1.27796587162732));
#631=CARTESIAN_POINT('',(-32.1526956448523,13.8277553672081,-1.18144289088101));
#632=CARTESIAN_POINT('',(-32.1931508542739,13.733304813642,-0.996785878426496));
#633=CARTESIAN_POINT('',(-32.2162311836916,13.6791349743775,-0.908656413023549));
#634=CARTESIAN_POINT('',(-32.2680543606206,13.5564469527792,-0.739530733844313));
#635=CARTESIAN_POINT('',(-32.2969763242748,13.4874689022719,-0.65892325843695));
#636=CARTESIAN_POINT('',(-32.3587440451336,13.3385972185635,-0.510290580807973));
#637=CARTESIAN_POINT('',(-32.3915910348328,13.2587001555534,-0.442269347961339));
#638=CARTESIAN_POINT('',(-32.4627646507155,13.0835206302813,-0.31519042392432));
#639=CARTESIAN_POINT('',(-32.5013188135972,12.9875244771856,-0.257243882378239));
#640=CARTESIAN_POINT('',(-32.5803880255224,12.7878792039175,-0.158353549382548));
#641=CARTESIAN_POINT('',(-32.6209034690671,12.6842285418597,-0.117413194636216));
#642=CARTESIAN_POINT('',(-32.6978539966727,12.4844050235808,-0.0570846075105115));
#643=CARTESIAN_POINT('',(-32.7342075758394,12.3887894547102,-0.0357257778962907));
#644=CARTESIAN_POINT('',(-32.8067116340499,12.195512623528,-0.00718045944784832));
#645=CARTESIAN_POINT('',(-32.8428622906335,12.0978536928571,2.13781106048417E-05));
#646=CARTESIAN_POINT('',(-32.8785644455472,12.,0.));
#647=B_SPLINE_CURVE_WITH_KNOTS('',3,(#621,#622,#623,#624,#625,#626,#627,#628,#629,#630,#631,
#632,#633,#634,#635,#636,#637,#638,#639,#640,#641,#642,#643,#644,#645,#646),.UNSPECIFIED.,.F.,
.F.,(4,2,2,2,2,2,2,2,2,2,2,2,4),(0.,0.159003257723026,0.317967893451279,0.476430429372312,
0.634897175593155,0.951398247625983,1.26807053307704,1.59655595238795,1.92514479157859,
2.27933253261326,2.63359181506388,2.94612292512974,3.25831500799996),.UNSPECIFIED.);
#648=EDGE_CURVE('E500',#219,#418,#647,.T.);
#649=ORIENTED_EDGE('',*,*,#648,.T.);
#650=ORIENTED_EDGE('',*,*,#421,.T.);
#651=CARTESIAN_POINT('',(-34.4818792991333,6.,0.));
#652=CARTESIAN_POINT('',(-34.4917063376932,5.94352869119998,-7.76788104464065E-07));
#653=CARTESIAN_POINT('',(-34.5013884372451,5.88705891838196,-0.00239329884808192));
#654=CARTESIAN_POINT('',(-34.5204112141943,5.77446640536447,-0.011953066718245));
#655=CARTESIAN_POINT('',(-34.5297518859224,5.7183436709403,-0.0191203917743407));
#656=CARTESIAN_POINT('',(-34.557162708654,5.55114441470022,-0.0477491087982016));
#657=CARTESIAN_POINT('',(-34.5746447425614,5.44110401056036,-0.0763372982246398));
#658=CARTESIAN_POINT('',(-34.6076382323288,5.22715369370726,-0.151864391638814));
#659=CARTESIAN_POINT('',(-34.6231481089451,5.12324872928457,-0.198817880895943));
#660=CARTESIAN_POINT('',(-34.6519457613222,4.9247047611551,-0.309833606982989));
#661=CARTESIAN_POINT('',(-34.6652343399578,4.83006241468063,-0.373889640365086));
#662=CARTESIAN_POINT('',(-34.6893488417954,4.65370223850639,-0.516679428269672));
#663=CARTESIAN_POINT('',(-34.700196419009,4.5718728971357,-0.595271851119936));
#664=CARTESIAN_POINT('',(-34.7195466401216,4.42252945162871,-0.765337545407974));
#665=CARTESIAN_POINT('',(-34.7280488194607,4.35501818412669,-0.856813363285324));
#666=CARTESIAN_POINT('',(-34.7426519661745,4.2369392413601,-1.04908854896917));
#667=CARTESIAN_POINT('',(-34.748774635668,4.18621908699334,-1.1497927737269));
#668=CARTESIAN_POINT('',(-34.7587706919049,4.10239616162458,-1.35835493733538));
#669=CARTESIAN_POINT('',(-34.7626456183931,4.06928133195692,-1.46620792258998));
#670=CARTESIAN_POINT('',(-34.767176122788,4.03034642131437,-1.6456632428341));
#671=CARTESIAN_POINT('',(-34.7684908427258,4.01897295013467,-1.71609353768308));
#672=CARTESIAN_POINT('',(-34.770240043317,4.00380132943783,-1.85767229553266));
#673=CARTESIAN_POINT('',(-34.7706758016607,3.99999218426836,-1.92881956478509));
#674=CARTESIAN_POINT('',(-34.7706773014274,4.,-2.));
#675=B_SPLINE_CURVE_WITH_KNOTS('',3,(#651,#652,#653,#654,#655,#656,#657,#658,#659,#660,#661,
#662,#663,#664,#665,#666,#667,#668,#669,#670,#671,#672,#673,#674),.UNSPECIFIED.,.F.,.F.,(4,2,2,
2,2,2,2,2,2,2,2,4),(0.,0.171856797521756,0.343716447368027,0.687036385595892,1.03062953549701,
1.37409822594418,1.71438805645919,2.05474524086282,2.39192098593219,2.72886548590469,
2.94254969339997,3.15592305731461),.UNSPECIFIED.);
#676=EDGE_CURVE('E417',#420,#166,#675,.T.);
#677=ORIENTED_EDGE('',*,*,#676,.T.);
#678=ORIENTED_EDGE('',*,*,#169,.T.);
#679=ORIENTED_EDGE('',*,*,#193,.T.);
#680=ORIENTED_EDGE('',*,*,#55,.T.);
#681=ORIENTED_EDGE('',*,*,#149,.T.);
#682=CARTESIAN_POINT('',(-34.7706773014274,-4.,-2.));
#683=CARTESIAN_POINT('',(-34.770676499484,-4.00000018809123,-1.94404006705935));
#684=CARTESIAN_POINT('',(-34.7704070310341,-4.00235013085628,-1.88810699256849));
#685=CARTESIAN_POINT('',(-34.7693270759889,-4.01172376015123,-1.77664227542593));
#686=CARTESIAN_POINT('',(-34.7685166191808,-4.01874718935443,-1.72111061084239));
#687=CARTESIAN_POINT('',(-34.7652720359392,-4.0467562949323,-1.55582564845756));
#688=CARTESIAN_POINT('',(-34.7620247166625,-4.07468100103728,-1.44718144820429));
#689=CARTESIAN_POINT('',(-34.7533243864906,-4.14822840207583,-1.23616117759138));
#690=CARTESIAN_POINT('',(-34.7478703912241,-4.1938589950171,-1.13378792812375));
#691=CARTESIAN_POINT('',(-34.7347132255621,-4.30146761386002,-0.93819121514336));
#692=CARTESIAN_POINT('',(-34.7270103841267,-4.36344324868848,-0.844966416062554));
#693=CARTESIAN_POINT('',(-34.7093131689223,-4.50205004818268,-0.670105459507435));
#694=CARTESIAN_POINT('',(-34.6993145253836,-4.57870847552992,-0.588491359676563));
#695=CARTESIAN_POINT('',(-34.6770513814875,-4.7443732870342,-0.439285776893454));
#696=CARTESIAN_POINT('',(-34.6647864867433,-4.83338181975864,-0.371696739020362));
#697=CARTESIAN_POINT('',(-34.6380026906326,-5.02173930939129,-0.251989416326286));
#698=CARTESIAN_POINT('',(-34.6234700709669,-5.12114989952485,-0.199971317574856));
#699=CARTESIAN_POINT('',(-34.592399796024,-5.32697713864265,-0.113337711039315));
#700=CARTESIAN_POINT('',(-34.5758628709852,-5.43339122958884,-0.078715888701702));
#701=CARTESIAN_POINT('',(-34.5464284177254,-5.61694672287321,-0.0355031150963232));
#702=CARTESIAN_POINT('',(-34.5339655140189,-5.69308232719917,-0.0221886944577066));
#703=CARTESIAN_POINT('',(-34.508384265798,-5.84615233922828,-0.00443801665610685));
#704=CARTESIAN_POINT('',(-34.4952669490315,-5.92308535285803,1.17387582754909E-05));
#705=CARTESIAN_POINT('',(-34.4818792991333,-6.,0.));
#706=B_SPLINE_CURVE_WITH_KNOTS('',3,(#682,#683,#684,#685,#686,#687,#688,#689,#690,#691,#692,
#693,#694,#695,#696,#697,#698,#699,#700,#701,#702,#703,#704,#705),.UNSPECIFIED.,.F.,.F.,(4,2,2,
2,2,2,2,2,2,2,2,4),(0.,0.167776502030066,0.335543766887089,0.670483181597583,1.00557217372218,
1.34061217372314,1.67628040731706,2.0120071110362,2.34984966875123,2.68756950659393,
2.92195601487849,3.15598534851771),.UNSPECIFIED.);
#707=EDGE_CURVE('E414',#142,#460,#706,.T.);
#708=ORIENTED_EDGE('',*,*,#707,.T.);
#709=ORIENTED_EDGE('',*,*,#463,.T.);
#710=CARTESIAN_POINT('',(-32.8785644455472,-12.,0.));
#711=CARTESIAN_POINT('',(-32.8567375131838,-12.0598059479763,-2.54975750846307E-06));
#712=CARTESIAN_POINT('',(-32.8347564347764,-12.1195214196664,-0.00268385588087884));
#713=CARTESIAN_POINT('',(-32.7906280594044,-12.238411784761,-0.0133628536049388));
#714=CARTESIAN_POINT('',(-32.7684807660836,-12.2975866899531,-0.0213604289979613));
#715=CARTESIAN_POINT('',(-32.7020073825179,-12.4737487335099,-0.0532630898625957));
#716=CARTESIAN_POINT('',(-32.6576436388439,-12.5893900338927,-0.0850781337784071));
#717=CARTESIAN_POINT('',(-32.5703141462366,-12.8136318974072,-0.169053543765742));
#718=CARTESIAN_POINT('',(-32.5273492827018,-12.9222280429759,-0.221226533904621));
#719=CARTESIAN_POINT('',(-32.4443956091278,-13.1291129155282,-0.344825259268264));
#720=CARTESIAN_POINT('',(-32.4044055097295,-13.2274061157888,-0.416242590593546));
#721=CARTESIAN_POINT('',(-32.3299365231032,-13.4083774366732,-0.574994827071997));
#722=CARTESIAN_POINT('',(-32.2953544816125,-13.4913553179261,-0.661938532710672));
#723=CARTESIAN_POINT('',(-32.232331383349,-13.6412405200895,-0.850724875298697));
#724=CARTESIAN_POINT('',(-32.2038894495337,-13.7081501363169,-0.952565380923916));
#725=CARTESIAN_POINT('',(-32.1565315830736,-13.8188588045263,-1.16056427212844));
#726=CARTESIAN_POINT('',(-32.1370855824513,-13.8639542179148,-1.26591258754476));
#727=CARTESIAN_POINT('',(-32.1060821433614,-13.9356033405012,-1.48374243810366));
#728=CARTESIAN_POINT('',(-32.0945098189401,-13.9621920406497,-1.59621007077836));
#729=CARTESIAN_POINT('',(-32.0841707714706,-13.9859225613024,-1.75818304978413));
#730=CARTESIAN_POINT('',(-32.0818694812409,-13.9911996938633,-1.80639970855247));
#731=CARTESIAN_POINT('',(-32.0788001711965,-13.9982352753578,-1.9030686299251));
#732=CARTESIAN_POINT('',(-32.0780299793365,-13.9999987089,-1.95152046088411));
#733=CARTESIAN_POINT('',(-32.0780298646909,-14.,-2.));
#734=B_SPLINE_CURVE_WITH_KNOTS('',3,(#710,#711,#712,#713,#714,#715,#716,#717,#718,#719,#720,
#721,#722,#723,#724,#725,#726,#727,#728,#729,#730,#731,#732,#733),.UNSPECIFIED.,.F.,.F.,(4,2,2,
2,2,2,2,2,2,2,2,4),(0.,0.190873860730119,0.38174354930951,0.763429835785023,1.14535318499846,
1.5271100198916,1.90033924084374,2.27351511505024,2.6203923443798,2.96661193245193,
3.11216426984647,3.25750997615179),.UNSPECIFIED.);
#735=EDGE_CURVE('E398',#462,#345,#734,.T.);
#736=ORIENTED_EDGE('',*,*,#735,.T.);
#737=ORIENTED_EDGE('',*,*,#346,.F.);
#738=ORIENTED_EDGE('',*,*,#383,.T.);
#739=ORIENTED_EDGE('',*,*,#322,.F.);
#740=CARTESIAN_POINT('',(-27.2213151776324,-22.,-2.));
#741=CARTESIAN_POINT('',(-27.2213222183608,-21.9999899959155,-1.95280063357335));
#742=CARTESIAN_POINT('',(-27.2199650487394,-22.0016705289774,-1.90560753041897));
#743=CARTESIAN_POINT('',(-27.2145764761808,-22.0083361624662,-1.81163213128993));
#744=CARTESIAN_POINT('',(-27.210546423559,-22.0133195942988,-1.76484963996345));
#745=CARTESIAN_POINT('',(-27.1998984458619,-22.0264747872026,-1.67232577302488));
#746=CARTESIAN_POINT('',(-27.1932963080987,-22.0346270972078,-1.62657981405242));
#747=CARTESIAN_POINT('',(-27.1776070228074,-22.0539754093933,-1.53618088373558));
#748=CARTESIAN_POINT('',(-27.1685196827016,-22.0651716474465,-1.49152799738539));
#749=CARTESIAN_POINT('',(-27.1377406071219,-22.1030337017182,-1.35982018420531));
#750=CARTESIAN_POINT('',(-27.1125030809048,-22.1340085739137,-1.2747732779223));
#751=CARTESIAN_POINT('',(-27.0537782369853,-22.2057474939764,-1.11196467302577));
#752=CARTESIAN_POINT('',(-27.0202798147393,-22.2465247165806,-1.03421297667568));
#753=CARTESIAN_POINT('',(-26.9437634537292,-22.3391461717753,-0.881946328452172));
#754=CARTESIAN_POINT('',(-26.9002449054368,-22.3915634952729,-0.808034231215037));
#755=CARTESIAN_POINT('',(-26.8067869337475,-22.5033664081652,-0.670351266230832));
#756=CARTESIAN_POINT('',(-26.7568467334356,-22.5627528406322,-0.606581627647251));
#757=CARTESIAN_POINT('',(-26.6248974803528,-22.7184911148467,-0.459091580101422));
#758=CARTESIAN_POINT('',(-26.539560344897,-22.8182018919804,-0.381872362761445));
#759=CARTESIAN_POINT('',(-26.3603969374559,-23.0249493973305,-0.2494477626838));
#760=CARTESIAN_POINT('',(-26.2665372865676,-23.1320144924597,-0.19433395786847));
#761=CARTESIAN_POINT('',(-26.1144699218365,-23.3032506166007,-0.124074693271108));
#762=CARTESIAN_POINT('',(-26.0580900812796,-23.3662840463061,-0.101901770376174));
#763=CARTESIAN_POINT('',(-25.9438580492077,-23.4930521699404,-0.0641855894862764));
#764=CARTESIAN_POINT('',(-25.8860053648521,-23.5567870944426,-0.0486445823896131));
#765=CARTESIAN_POINT('',(-25.7697572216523,-23.6838965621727,-0.0240867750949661));
#766=CARTESIAN_POINT('',(-25.7113717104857,-23.747268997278,-0.0150110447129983));
#767=CARTESIAN_POINT('',(-25.5938924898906,-23.8738383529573,-0.00297434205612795));
#768=CARTESIAN_POINT('',(-25.5347994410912,-23.9370353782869,-8.05451721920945E-06));
#769=CARTESIAN_POINT('',(-25.475478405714,-24.,0.));
#770=B_SPLINE_CURVE_WITH_KNOTS('',3,(#740,#741,#742,#743,#744,#745,#746,#747,#748,#749,#750,
#751,#752,#753,#754,#755,#756,#757,#758,#759,#760,#761,#762,#763,#764,#765,#766,#767,#768,#769),
.UNSPECIFIED.,.F.,.F.,(4,2,2,2,2,2,2,2,2,2,2,2,2,2,4),(0.,0.141538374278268,0.283005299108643,
0.423617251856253,0.56424010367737,0.844754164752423,1.12564737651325,1.42610944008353,
1.72660788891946,2.18095596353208,2.63716732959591,2.89921476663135,3.16135107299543,
3.42106635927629,3.68055559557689),.UNSPECIFIED.);
#771=EDGE_CURVE('E372',#313,#403,#770,.T.);
#772=ORIENTED_EDGE('',*,*,#771,.T.);
#773=ORIENTED_EDGE('',*,*,#406,.T.);
#774=CARTESIAN_POINT('',(25.475478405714,-24.,0.));
#775=CARTESIAN_POINT('',(25.533136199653,-23.9388004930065,-7.24315117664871E-06));
#776=CARTESIAN_POINT('',(25.5905781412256,-23.8773823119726,-0.00280986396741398));
#777=CARTESIAN_POINT('',(25.7047973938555,-23.7543765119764,-0.0141763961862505));
#778=CARTESIAN_POINT('',(25.7615741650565,-23.6927887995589,-0.022744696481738));
#779=CARTESIAN_POINT('',(25.874579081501,-23.5693279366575,-0.0459033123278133));
#780=CARTESIAN_POINT('',(25.9307995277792,-23.5074562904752,-0.0605399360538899));
#781=CARTESIAN_POINT('',(26.0418851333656,-23.3843345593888,-0.0960406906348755));
#782=CARTESIAN_POINT('',(26.0967506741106,-23.3230843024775,-0.116903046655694));
#783=CARTESIAN_POINT('',(26.2464819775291,-23.1547582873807,-0.183694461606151));
#784=CARTESIAN_POINT('',(26.3395887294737,-23.0487442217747,-0.236550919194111));
#785=CARTESIAN_POINT('',(26.5177862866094,-22.8434981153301,-0.363837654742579));
#786=CARTESIAN_POINT('',(26.6028992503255,-22.744247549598,-0.438205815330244));
#787=CARTESIAN_POINT('',(26.744639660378,-22.5772791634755,-0.590843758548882));
#788=CARTESIAN_POINT('',(26.8034317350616,-22.5074044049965,-0.664727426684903));
#789=CARTESIAN_POINT('',(26.9121598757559,-22.3772836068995,-0.826322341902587));
#790=CARTESIAN_POINT('',(26.9621030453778,-22.3170298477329,-0.914022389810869));
#791=CARTESIAN_POINT('',(27.0432813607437,-22.2185579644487,-1.08643358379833));
#792=CARTESIAN_POINT('',(27.0762491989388,-22.1783390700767,-1.16918059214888));
#793=CARTESIAN_POINT('',(27.1328826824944,-22.109018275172,-1.34210029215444));
#794=CARTESIAN_POINT('',(27.1565642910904,-22.0798972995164,-1.43225991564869));
#795=CARTESIAN_POINT('',(27.1901715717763,-22.0384925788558,-1.60162359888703));
#796=CARTESIAN_POINT('',(27.2017777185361,-22.0241560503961,-1.67998962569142));
#797=CARTESIAN_POINT('',(27.2134615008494,-22.0097148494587,-1.79905868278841));
#798=CARTESIAN_POINT('',(27.2164019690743,-22.0060782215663,-1.83908957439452));
#799=CARTESIAN_POINT('',(27.2203301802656,-22.0012188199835,-1.91940869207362));
#800=CARTESIAN_POINT('',(27.2213171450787,-21.9999970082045,-1.95969701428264));
#801=CARTESIAN_POINT('',(27.2213151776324,-22.,-2.));
#802=B_SPLINE_CURVE_WITH_KNOTS('',3,(#774,#775,#776,#777,#778,#779,#780,#781,#782,#783,#784,
#785,#786,#787,#788,#789,#790,#791,#792,#793,#794,#795,#796,#797,#798,#799,#800,#801),
.UNSPECIFIED.,.F.,.F.,(4,2,2,2,2,2,2,2,2,2,2,2,2,4),(0.,0.252215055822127,0.504622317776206,
0.758992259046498,1.01328975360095,1.46356423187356,1.91255125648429,2.26364318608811,
2.61445198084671,2.90644391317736,3.19793168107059,3.43849242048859,3.55929428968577,
3.68014426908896),.UNSPECIFIED.);
#803=EDGE_CURVE('E378',#405,#305,#802,.T.);
#804=ORIENTED_EDGE('',*,*,#803,.T.);
#805=ORIENTED_EDGE('',*,*,#306,.F.);
#806=ORIENTED_EDGE('',*,*,#386,.T.);
#807=ORIENTED_EDGE('',*,*,#362,.F.);
#808=CARTESIAN_POINT('',(32.0780298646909,-14.,-2.));
#809=CARTESIAN_POINT('',(32.0780254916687,-14.0000076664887,-1.94697972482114));
#810=CARTESIAN_POINT('',(32.0789499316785,-13.9978918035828,-1.89396375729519));
#811=CARTESIAN_POINT('',(32.082623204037,-13.9894720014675,-1.788341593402));
#812=CARTESIAN_POINT('',(32.0853715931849,-13.9831690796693,-1.73573530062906));
#813=CARTESIAN_POINT('',(32.0926480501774,-13.9664605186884,-1.63147242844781));
#814=CARTESIAN_POINT('',(32.0971704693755,-13.9560679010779,-1.57981337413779));
#815=CARTESIAN_POINT('',(32.1079280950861,-13.9313005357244,-1.47765459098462));
#816=CARTESIAN_POINT('',(32.1141633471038,-13.9169256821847,-1.42715489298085));
#817=CARTESIAN_POINT('',(32.1353176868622,-13.8680435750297,-1.27796587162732));
#818=CARTESIAN_POINT('',(32.1526956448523,-13.8277553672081,-1.18144289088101));
#819=CARTESIAN_POINT('',(32.1931508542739,-13.733304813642,-0.996785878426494));
#820=CARTESIAN_POINT('',(32.2162311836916,-13.6791349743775,-0.908656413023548));
#821=CARTESIAN_POINT('',(32.2680543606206,-13.5564469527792,-0.739530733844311));
#822=CARTESIAN_POINT('',(32.2969763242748,-13.4874689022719,-0.658923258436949));
#823=CARTESIAN_POINT('',(32.3587440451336,-13.3385972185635,-0.510290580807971));
#824=CARTESIAN_POINT('',(32.3915910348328,-13.2587001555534,-0.442269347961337));
#825=CARTESIAN_POINT('',(32.4627646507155,-13.0835206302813,-0.315190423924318));
#826=CARTESIAN_POINT('',(32.5013188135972,-12.9875244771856,-0.257243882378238));
#827=CARTESIAN_POINT('',(32.5803880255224,-12.7878792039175,-0.158353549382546));
#828=CARTESIAN_POINT('',(32.6209034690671,-12.6842285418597,-0.117413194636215));
#829=CARTESIAN_POINT('',(32.6978539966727,-12.4844050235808,-0.0570846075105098));
#830=CARTESIAN_POINT('',(32.7342075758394,-12.3887894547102,-0.035725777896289));
#831=CARTESIAN_POINT('',(32.8067116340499,-12.195512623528,-0.00718045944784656));
#832=CARTESIAN_POINT('',(32.8428622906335,-12.0978536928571,2.13781106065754E-05));
#833=CARTESIAN_POINT('',(32.8785644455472,-12.,0.));
#834=B_SPLINE_CURVE_WITH_KNOTS('',3,(#808,#809,#810,#811,#812,#813,#814,#815,#816,#817,#818,
#819,#820,#821,#822,#823,#824,#825,#826,#827,#828,#829,#830,#831,#832,#833),.UNSPECIFIED.,.F.,
.F.,(4,2,2,2,2,2,2,2,2,2,2,2,4),(0.,0.159003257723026,0.317967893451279,0.476430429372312,
0.634897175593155,0.951398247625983,1.26807053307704,1.59655595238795,1.92514479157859,
2.27933253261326,2.63359181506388,2.94612292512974,3.25831500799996),.UNSPECIFIED.);
#835=EDGE_CURVE('E403',#353,#474,#834,.T.);
#836=ORIENTED_EDGE('',*,*,#835,.T.);
#837=ORIENTED_EDGE('',*,*,#475,.T.);
#838=CARTESIAN_POINT('',(34.4818792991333,-6.,0.));
#839=CARTESIAN_POINT('',(34.4917063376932,-5.94352869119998,-7.76788104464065E-07));
#840=CARTESIAN_POINT('',(34.5013884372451,-5.88705891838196,-0.00239329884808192));
#841=CARTESIAN_POINT('',(34.5204112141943,-5.77446640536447,-0.011953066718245));
#842=CARTESIAN_POINT('',(34.5297518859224,-5.7183436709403,-0.0191203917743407));
#843=CARTESIAN_POINT('',(34.557162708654,-5.55114441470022,-0.0477491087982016));
#844=CARTESIAN_POINT('',(34.5746447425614,-5.44110401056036,-0.0763372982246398));
#845=CARTESIAN_POINT('',(34.6076382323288,-5.22715369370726,-0.151864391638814));
#846=CARTESIAN_POINT('',(34.6231481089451,-5.12324872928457,-0.198817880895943));
#847=CARTESIAN_POINT('',(34.6519457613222,-4.9247047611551,-0.309833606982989));
#848=CARTESIAN_POINT('',(34.6652343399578,-4.83006241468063,-0.373889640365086));
#849=CARTESIAN_POINT('',(34.6893488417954,-4.65370223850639,-0.516679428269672));
#850=CARTESIAN_POINT('',(34.700196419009,-4.5718728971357,-0.595271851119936));
#851=CARTESIAN_POINT('',(34.7195466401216,-4.42252945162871,-0.765337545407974));
#852=CARTESIAN_POINT('',(34.7280488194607,-4.35501818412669,-0.856813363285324));
#853=CARTESIAN_POINT('',(34.7426519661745,-4.2369392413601,-1.04908854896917));
#854=CARTESIAN_POINT('',(34.748774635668,-4.18621908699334,-1.1497927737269));
#855=CARTESIAN_POINT('',(34.7587706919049,-4.10239616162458,-1.35835493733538));
#856=CARTESIAN_POINT('',(34.7626456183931,-4.06928133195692,-1.46620792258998));
#857=CARTESIAN_POINT('',(34.767176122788,-4.03034642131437,-1.6456632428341));
#858=CARTESIAN_POINT('',(34.7684908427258,-4.01897295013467,-1.71609353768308));
#859=CARTESIAN_POINT('',(34.770240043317,-4.00380132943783,-1.85767229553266));
#860=CARTESIAN_POINT('',(34.7706758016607,-3.99999218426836,-1.92881956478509));
#861=CARTESIAN_POINT('',(34.7706773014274,-4.,-2.));
#862=B_SPLINE_CURVE_WITH_KNOTS('',3,(#838,#839,#840,#841,#842,#843,#844,#845,#846,#847,#848,
#849,#850,#851,#852,#853,#854,#855,#856,#857,#858,#859,#860,#861),.UNSPECIFIED.,.F.,.F.,(4,2,2,
2,2,2,2,2,2,2,2,4),(0.,0.171856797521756,0.343716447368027,0.687036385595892,1.03062953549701,
1.37409822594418,1.71438805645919,2.05474524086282,2.39192098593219,2.72886548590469,
2.94254969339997,3.15592305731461),.UNSPECIFIED.);
#863=EDGE_CURVE('E411',#470,#134,#862,.T.);
#864=ORIENTED_EDGE('',*,*,#863,.T.);
#865=ORIENTED_EDGE('',*,*,#135,.T.);
#866=ORIENTED_EDGE('',*,*,#70,.T.);
#867=ORIENTED_EDGE('',*,*,#80,.T.);
#868=EDGE_LOOP('',(#494,#521,#522,#549,#550,#551,#552,#585,#586,#617,#618,#619,#620,#649,#650,
#677,#678,#679,#680,#681,#708,#709,#736,#737,#738,#739,#772,#773,#804,#805,#806,#807,#836,#837,
#864,#865,#866,#867));
#869=FACE_BOUND('',#868,.T.);
#870=ADVANCED_FACE('F41',(#493,#869),#490,.T.);
#871=ORIENTED_EDGE('',*,*,#119,.F.);
#872=EDGE_LOOP('',(#871));
#873=FACE_BOUND('',#872,.T.);
#874=ADVANCED_FACE('F296',(#873),#100,.T.);
#875=CARTESIAN_POINT('',(43.,24.,-2.));
#876=DIRECTION('',(-1.,0.,0.));
#877=DIRECTION('',(0.,0.,1.));
#878=AXIS2_PLACEMENT_3D('',#875,#876,#877);
#879=CYLINDRICAL_SURFACE('',#878,2.);
#880=ORIENTED_EDGE('',*,*,#616,.F.);
#881=ORIENTED_EDGE('',*,*,#454,.F.);
#882=ORIENTED_EDGE('',*,*,#584,.F.);
#883=ORIENTED_EDGE('',*,*,#260,.F.);
#884=EDGE_LOOP('',(#880,#881,#882,#883));
#885=FACE_BOUND('',#884,.T.);
#886=ADVANCED_FACE('F290',(#885),#879,.F.);
#887=CARTESIAN_POINT('',(43.,12.,-2.));
#888=DIRECTION('',(1.,0.,0.));
#889=DIRECTION('',(0.,0.,-1.));
#890=AXIS2_PLACEMENT_3D('',#887,#888,#889);
#891=CYLINDRICAL_SURFACE('',#890,2.);
#892=ORIENTED_EDGE('',*,*,#548,.F.);
#893=ORIENTED_EDGE('',*,*,#429,.F.);
#894=ORIENTED_EDGE('',*,*,#648,.F.);
#895=ORIENTED_EDGE('',*,*,#220,.F.);
#896=EDGE_LOOP('',(#892,#893,#894,#895));
#897=FACE_BOUND('',#896,.T.);
#898=ADVANCED_FACE('F295',(#897),#891,.F.);
#899=CARTESIAN_POINT('',(43.,6.,-2.));
#900=DIRECTION('',(-1.,0.,0.));
#901=DIRECTION('',(0.,0.,1.));
#902=AXIS2_PLACEMENT_3D('',#899,#900,#901);
#903=CYLINDRICAL_SURFACE('',#902,2.);
#904=ORIENTED_EDGE('',*,*,#676,.F.);
#905=ORIENTED_EDGE('',*,*,#439,.F.);
#906=ORIENTED_EDGE('',*,*,#520,.F.);
#907=ORIENTED_EDGE('',*,*,#177,.F.);
#908=EDGE_LOOP('',(#904,#905,#906,#907));
#909=FACE_BOUND('',#908,.T.);
#910=ADVANCED_FACE('F435',(#909),#903,.F.);
#911=CARTESIAN_POINT('',(43.,-6.,-2.));
#912=DIRECTION('',(1.,0.,0.));
#913=DIRECTION('',(0.,0.,-1.));
#914=AXIS2_PLACEMENT_3D('',#911,#912,#913);
#915=CYLINDRICAL_SURFACE('',#914,2.);
#916=ORIENTED_EDGE('',*,*,#863,.F.);
#917=ORIENTED_EDGE('',*,*,#471,.F.);
#918=ORIENTED_EDGE('',*,*,#707,.F.);
#919=ORIENTED_EDGE('',*,*,#143,.F.);
#920=EDGE_LOOP('',(#916,#917,#918,#919));
#921=FACE_BOUND('',#920,.T.);
#922=ADVANCED_FACE('F393',(#921),#915,.F.);
#923=CARTESIAN_POINT('',(0.,-12.,-2.));
#924=DIRECTION('',(-1.,0.,0.));
#925=DIRECTION('',(0.,0.,1.));
#926=AXIS2_PLACEMENT_3D('',#923,#924,#925);
#927=CYLINDRICAL_SURFACE('',#926,2.);
#928=ORIENTED_EDGE('',*,*,#835,.F.);
#929=ORIENTED_EDGE('',*,*,#354,.F.);
#930=ORIENTED_EDGE('',*,*,#735,.F.);
#931=ORIENTED_EDGE('',*,*,#481,.F.);
#932=EDGE_LOOP('',(#928,#929,#930,#931));
#933=FACE_BOUND('',#932,.T.);
#934=ADVANCED_FACE('F387',(#933),#927,.F.);
#935=CARTESIAN_POINT('',(0.,-24.,-2.));
#936=DIRECTION('',(1.,0.,0.));
#937=DIRECTION('',(0.,0.,-1.));
#938=AXIS2_PLACEMENT_3D('',#935,#936,#937);
#939=CYLINDRICAL_SURFACE('',#938,2.);
#940=ORIENTED_EDGE('',*,*,#771,.F.);
#941=ORIENTED_EDGE('',*,*,#314,.F.);
#942=ORIENTED_EDGE('',*,*,#803,.F.);
#943=ORIENTED_EDGE('',*,*,#412,.F.);
#944=EDGE_LOOP('',(#940,#941,#942,#943));
#945=FACE_BOUND('',#944,.T.);
#946=ADVANCED_FACE('F383',(#945),#939,.F.);
#947=CLOSED_SHELL('',(#59,#77,#95,#123,#155,#190,#198,#238,#278,#292,#332,#372,#391,#416,#443,
#458,#485,#870,#874,#886,#898,#910,#922,#934,#946));
#948=MANIFOLD_SOLID_BREP('B2',#947);
#949=ADVANCED_BREP_SHAPE_REPRESENTATION('',(#18,#948),#14);
#950=SHAPE_DEFINITION_REPRESENTATION(#9,#949);
ENDSEC;
END-ISO-10303-21;
